VERSION 5.8 ;
BUSBITCHARS "[]" ;
DIVIDERCHAR "/" ;
UNITS
    DATABASE MICRONS 1000 ;
END UNITS

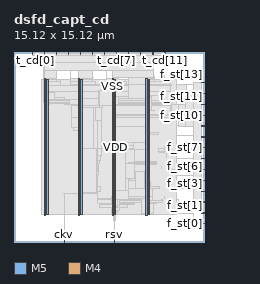
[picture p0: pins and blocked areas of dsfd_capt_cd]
MACRO dsfd_capt_cd
  FOREIGN dsfd_capt_cd 0 0 ;
  CLASS BLOCK ;
  SIZE 15.12 BY 15.12 ;
  PIN ckv
    DIRECTION INPUT ;
    USE SIGNAL ;
    PORT
      LAYER M5 ;
        RECT  3.984 0 4.008 0.192 ;
    END
  END ckv
  PIN f_st[0]
    DIRECTION INPUT ;
    USE SIGNAL ;
    PORT
      LAYER M4 ;
        RECT  14.928 1.44 15.12 1.464 ;
    END
  END f_st[0]
  PIN f_st[10]
    DIRECTION INPUT ;
    USE SIGNAL ;
    PORT
      LAYER M4 ;
        RECT  14.928 10.08 15.12 10.104 ;
    END
  END f_st[10]
  PIN f_st[11]
    DIRECTION INPUT ;
    USE SIGNAL ;
    PORT
      LAYER M4 ;
        RECT  14.928 10.944 15.12 10.968 ;
    END
  END f_st[11]
  PIN f_st[12]
    DIRECTION INPUT ;
    USE SIGNAL ;
    PORT
      LAYER M4 ;
        RECT  14.928 11.808 15.12 11.832 ;
    END
  END f_st[12]
  PIN f_st[13]
    DIRECTION INPUT ;
    USE SIGNAL ;
    PORT
      LAYER M4 ;
        RECT  14.928 12.672 15.12 12.696 ;
    END
  END f_st[13]
  PIN f_st[1]
    DIRECTION INPUT ;
    USE SIGNAL ;
    PORT
      LAYER M4 ;
        RECT  14.928 2.304 15.12 2.328 ;
    END
  END f_st[1]
  PIN f_st[2]
    DIRECTION INPUT ;
    USE SIGNAL ;
    PORT
      LAYER M4 ;
        RECT  14.928 3.168 15.12 3.192 ;
    END
  END f_st[2]
  PIN f_st[3]
    DIRECTION INPUT ;
    USE SIGNAL ;
    PORT
      LAYER M4 ;
        RECT  14.928 4.032 15.12 4.056 ;
    END
  END f_st[3]
  PIN f_st[4]
    DIRECTION INPUT ;
    USE SIGNAL ;
    PORT
      LAYER M4 ;
        RECT  14.928 4.896 15.12 4.92 ;
    END
  END f_st[4]
  PIN f_st[5]
    DIRECTION INPUT ;
    USE SIGNAL ;
    PORT
      LAYER M4 ;
        RECT  14.928 5.76 15.12 5.784 ;
    END
  END f_st[5]
  PIN f_st[6]
    DIRECTION INPUT ;
    USE SIGNAL ;
    PORT
      LAYER M4 ;
        RECT  14.928 6.624 15.12 6.648 ;
    END
  END f_st[6]
  PIN f_st[7]
    DIRECTION INPUT ;
    USE SIGNAL ;
    PORT
      LAYER M4 ;
        RECT  14.928 7.488 15.12 7.512 ;
    END
  END f_st[7]
  PIN f_st[8]
    DIRECTION INPUT ;
    USE SIGNAL ;
    PORT
      LAYER M4 ;
        RECT  14.928 8.352 15.12 8.376 ;
    END
  END f_st[8]
  PIN f_st[9]
    DIRECTION INPUT ;
    USE SIGNAL ;
    PORT
      LAYER M4 ;
        RECT  14.928 9.216 15.12 9.24 ;
    END
  END f_st[9]
  PIN rsv
    DIRECTION INPUT ;
    USE SIGNAL ;
    PORT
      LAYER M5 ;
        RECT  7.968 0 7.992 0.192 ;
    END
  END rsv
  PIN t_cd[0]
    DIRECTION OUTPUT ;
    USE SIGNAL ;
    PORT
      LAYER M5 ;
        RECT  1.44 14.928 1.464 15.12 ;
    END
  END t_cd[0]
  PIN t_cd[10]
    DIRECTION OUTPUT ;
    USE SIGNAL ;
    PORT
      LAYER M5 ;
        RECT  11.04 14.928 11.064 15.12 ;
    END
  END t_cd[10]
  PIN t_cd[11]
    DIRECTION OUTPUT ;
    USE SIGNAL ;
    PORT
      LAYER M5 ;
        RECT  12 14.928 12.024 15.12 ;
    END
  END t_cd[11]
  PIN t_cd[1]
    DIRECTION OUTPUT ;
    USE SIGNAL ;
    PORT
      LAYER M5 ;
        RECT  2.4 14.928 2.424 15.12 ;
    END
  END t_cd[1]
  PIN t_cd[2]
    DIRECTION OUTPUT ;
    USE SIGNAL ;
    PORT
      LAYER M5 ;
        RECT  3.36 14.928 3.384 15.12 ;
    END
  END t_cd[2]
  PIN t_cd[3]
    DIRECTION OUTPUT ;
    USE SIGNAL ;
    PORT
      LAYER M5 ;
        RECT  4.32 14.928 4.344 15.12 ;
    END
  END t_cd[3]
  PIN t_cd[4]
    DIRECTION OUTPUT ;
    USE SIGNAL ;
    PORT
      LAYER M5 ;
        RECT  5.28 14.928 5.304 15.12 ;
    END
  END t_cd[4]
  PIN t_cd[5]
    DIRECTION OUTPUT ;
    USE SIGNAL ;
    PORT
      LAYER M5 ;
        RECT  6.24 14.928 6.264 15.12 ;
    END
  END t_cd[5]
  PIN t_cd[6]
    DIRECTION OUTPUT ;
    USE SIGNAL ;
    PORT
      LAYER M5 ;
        RECT  7.2 14.928 7.224 15.12 ;
    END
  END t_cd[6]
  PIN t_cd[7]
    DIRECTION OUTPUT ;
    USE SIGNAL ;
    PORT
      LAYER M5 ;
        RECT  8.16 14.928 8.184 15.12 ;
    END
  END t_cd[7]
  PIN t_cd[8]
    DIRECTION OUTPUT ;
    USE SIGNAL ;
    PORT
      LAYER M5 ;
        RECT  9.12 14.928 9.144 15.12 ;
    END
  END t_cd[8]
  PIN t_cd[9]
    DIRECTION OUTPUT ;
    USE SIGNAL ;
    PORT
      LAYER M5 ;
        RECT  10.08 14.928 10.104 15.12 ;
    END
  END t_cd[9]
  PIN VDD
    DIRECTION INOUT ;
    USE POWER ;
    PORT
      LAYER M5 ;
        RECT  10.692 2.151 10.812 12.969 ;
        RECT  7.992 2.151 8.112 12.969 ;
        RECT  5.292 2.151 5.412 12.969 ;
        RECT  2.592 2.151 2.712 12.969 ;
    END
  END VDD
  PIN VSS
    DIRECTION INOUT ;
    USE GROUND ;
    PORT
      LAYER M5 ;
        RECT  10.5 2.137 10.62 12.983 ;
        RECT  7.8 2.137 7.92 12.983 ;
        RECT  5.1 2.137 5.22 12.983 ;
        RECT  2.4 2.137 2.52 12.983 ;
    END
  END VSS
  OBS
    LAYER RVTN ;
     RECT  2.16 2.16 12.96 2.295 ;
     RECT  2.16 2.565 12.96 2.835 ;
     RECT  2.16 3.105 12.96 3.375 ;
     RECT  2.16 3.645 12.96 3.915 ;
     RECT  2.16 4.185 12.96 4.455 ;
     RECT  2.16 4.725 12.96 4.995 ;
     RECT  2.16 5.265 12.96 5.535 ;
     RECT  2.16 5.805 12.96 6.075 ;
     RECT  2.16 6.345 12.96 6.615 ;
     RECT  2.16 6.885 12.96 7.155 ;
     RECT  2.16 7.425 12.96 7.695 ;
     RECT  2.16 7.965 12.96 8.235 ;
     RECT  2.16 8.505 12.96 8.775 ;
     RECT  2.16 9.045 12.96 9.315 ;
     RECT  2.16 9.585 12.96 9.855 ;
     RECT  2.16 10.125 12.96 10.395 ;
     RECT  2.16 10.665 12.96 10.935 ;
     RECT  2.16 11.205 12.96 11.475 ;
     RECT  2.16 11.745 12.96 12.015 ;
     RECT  2.16 12.285 12.96 12.555 ;
     RECT  2.16 12.825 12.96 12.96 ;
    LAYER RVTP ;
     RECT  2.16 2.295 12.96 2.565 ;
     RECT  2.16 2.835 12.96 3.105 ;
     RECT  2.16 3.375 12.96 3.645 ;
     RECT  2.16 3.915 12.96 4.185 ;
     RECT  2.16 4.455 12.96 4.725 ;
     RECT  2.16 4.995 12.96 5.265 ;
     RECT  2.16 5.535 12.96 5.805 ;
     RECT  2.16 6.075 12.96 6.345 ;
     RECT  2.16 6.615 12.96 6.885 ;
     RECT  2.16 7.155 12.96 7.425 ;
     RECT  2.16 7.695 12.96 7.965 ;
     RECT  2.16 8.235 12.96 8.505 ;
     RECT  2.16 8.775 12.96 9.045 ;
     RECT  2.16 9.315 12.96 9.585 ;
     RECT  2.16 9.855 12.96 10.125 ;
     RECT  2.16 10.395 12.96 10.665 ;
     RECT  2.16 10.935 12.96 11.205 ;
     RECT  2.16 11.475 12.96 11.745 ;
     RECT  2.16 12.015 12.96 12.285 ;
     RECT  2.16 12.555 12.96 12.825 ;
    LAYER M1 ;
     RECT  2.16 2.151 12.96 12.969 ;
    LAYER M2 ;
     RECT  2.16 2.151 12.96 12.969 ;
     RECT  12.96 3.348 13.127 3.366 ;
     RECT  12.96 9.288 13.127 9.306 ;
     RECT  12.96 11.79 13.703 12.546 ;
     RECT  12.96 2.268 14.279 2.286 ;
     RECT  12.96 4.23 14.279 4.248 ;
     RECT  12.96 5.31 14.279 5.328 ;
     RECT  12.96 6.624 14.279 6.642 ;
     RECT  12.96 7.398 14.279 7.416 ;
     RECT  12.96 8.478 14.279 8.496 ;
     RECT  13.703 12.528 14.279 12.546 ;
    LAYER M3 ;
     RECT  8.028 1.723 8.046 2.143 ;
     RECT  7.815 2.143 8.046 2.191 ;
     RECT  10.515 2.143 10.605 2.191 ;
     RECT  10.515 2.191 10.674 2.227 ;
     RECT  10.188 2.227 11.07 2.285 ;
     RECT  14.256 1.435 14.274 2.291 ;
     RECT  7.74 2.191 8.046 2.371 ;
     RECT  2.415 2.143 2.505 2.413 ;
     RECT  5.115 2.143 5.205 2.413 ;
     RECT  7.74 2.371 8.226 2.533 ;
     RECT  7.74 2.533 8.37 2.767 ;
     RECT  6.84 2.767 9.018 3.001 ;
     RECT  6.84 3.001 9.558 3.029 ;
     RECT  10.332 2.285 11.07 3.037 ;
     RECT  7.38 3.029 9.558 3.065 ;
     RECT  7.56 3.065 9.558 3.101 ;
     RECT  7.74 3.101 9.558 3.109 ;
     RECT  10.332 3.037 11.322 3.109 ;
     RECT  7.74 3.109 11.322 3.181 ;
     RECT  7.74 3.181 11.79 3.335 ;
     RECT  13.104 3.163 13.122 3.371 ;
     RECT  11.772 3.335 11.79 3.407 ;
     RECT  7.74 3.335 11.034 3.605 ;
     RECT  7.815 3.605 8.19 3.641 ;
     RECT  11.952 3.451 11.97 3.641 ;
     RECT  7.815 3.641 8.154 3.749 ;
     RECT  6.624 3.037 6.642 3.835 ;
     RECT  6.336 3.835 6.642 3.875 ;
     RECT  6.552 3.875 6.642 3.965 ;
     RECT  6.624 3.965 6.642 3.991 ;
     RECT  9.108 3.605 11.034 4.261 ;
     RECT  9.108 4.261 11.574 4.289 ;
     RECT  10.404 4.289 11.574 4.379 ;
     RECT  6.624 3.991 6.858 4.415 ;
     RECT  10.404 4.379 10.89 4.793 ;
     RECT  7.815 3.749 8.097 4.891 ;
     RECT  9.108 4.289 9.666 4.891 ;
     RECT  7.815 4.891 9.666 5.027 ;
     RECT  7.815 5.027 8.586 5.213 ;
     RECT  14.256 4.027 14.274 5.333 ;
     RECT  6.624 4.415 6.642 5.341 ;
     RECT  9.612 5.027 9.666 5.611 ;
     RECT  10.404 4.793 10.797 5.611 ;
     RECT  6.588 5.341 6.714 5.639 ;
     RECT  12.564 5.755 12.582 5.801 ;
     RECT  11.736 5.881 11.754 5.999 ;
     RECT  7.815 5.213 8.406 6.151 ;
     RECT  9.612 5.611 10.797 6.151 ;
     RECT  6.624 5.639 6.714 6.241 ;
     RECT  7.815 6.151 8.766 6.241 ;
     RECT  9.612 6.151 11.358 6.241 ;
     RECT  7.815 6.241 11.358 6.269 ;
     RECT  9.144 6.269 11.358 6.341 ;
     RECT  9.612 6.341 11.358 6.413 ;
     RECT  6.624 6.241 6.786 6.511 ;
     RECT  14.256 6.613 14.274 6.653 ;
     RECT  6.624 6.511 6.894 6.853 ;
     RECT  12.132 6.691 12.15 7.079 ;
     RECT  11.592 7.087 11.97 7.231 ;
     RECT  8.856 7.321 8.874 7.387 ;
     RECT  9.612 6.413 10.797 7.387 ;
     RECT  11.52 7.231 11.97 7.421 ;
     RECT  7.815 6.269 8.097 7.435 ;
     RECT  8.856 7.387 10.797 7.435 ;
     RECT  14.256 7.393 14.274 7.517 ;
     RECT  11.952 7.421 11.97 7.619 ;
     RECT  7.815 7.435 10.797 7.655 ;
     RECT  14.256 8.347 14.274 8.501 ;
     RECT  9.072 7.655 10.797 8.581 ;
     RECT  7.815 7.655 8.097 8.671 ;
     RECT  9.072 8.581 11.502 8.735 ;
     RECT  5.115 2.413 5.397 8.851 ;
     RECT  7.815 8.671 8.118 8.851 ;
     RECT  9.072 8.735 10.797 8.851 ;
     RECT  4.752 8.851 5.397 9.085 ;
     RECT  13.104 9.211 13.122 9.311 ;
     RECT  6.624 6.853 7.002 9.661 ;
     RECT  11.7 9.859 11.718 9.895 ;
     RECT  12.492 9.391 12.51 9.895 ;
     RECT  4.572 9.085 5.397 9.931 ;
     RECT  7.815 8.851 10.797 9.931 ;
     RECT  11.7 9.895 12.51 9.931 ;
     RECT  7.815 9.931 12.51 10.075 ;
     RECT  7.815 10.075 12.582 10.121 ;
     RECT  6.48 9.661 7.002 10.741 ;
     RECT  4.572 9.931 5.742 10.831 ;
     RECT  6.48 10.741 7.038 10.831 ;
     RECT  4.572 10.831 7.038 10.843 ;
     RECT  7.815 10.121 12.438 10.843 ;
     RECT  2.415 2.413 2.697 10.939 ;
     RECT  4.572 10.843 12.438 10.939 ;
     RECT  4.392 10.939 12.582 10.975 ;
     RECT  2.415 10.939 2.862 11.011 ;
     RECT  3.996 10.975 12.582 11.011 ;
     RECT  2.415 11.011 12.582 11.101 ;
     RECT  2.34 11.101 12.582 11.237 ;
     RECT  13.68 11.785 13.698 11.837 ;
     RECT  2.34 11.237 12.474 11.975 ;
     RECT  2.376 11.975 12.474 12.451 ;
     RECT  2.376 12.451 12.546 12.479 ;
     RECT  4.464 12.479 12.546 12.551 ;
     RECT  7.38 12.551 12.474 12.557 ;
     RECT  14.256 12.523 14.274 12.701 ;
     RECT  2.376 12.479 3.726 12.749 ;
     RECT  4.464 12.551 6.498 12.749 ;
     RECT  7.38 12.557 8.946 12.749 ;
     RECT  9.684 12.557 12.474 12.749 ;
     RECT  4.464 12.749 6.246 12.785 ;
     RECT  2.376 12.749 2.505 12.901 ;
     RECT  3.384 12.749 3.726 12.929 ;
     RECT  10.188 12.749 11.142 12.929 ;
     RECT  2.34 12.901 2.505 12.977 ;
     RECT  4.464 12.785 5.454 12.977 ;
     RECT  7.38 12.749 8.334 12.977 ;
     RECT  10.515 12.929 11.142 12.977 ;
     RECT  3.384 12.929 3.402 13.085 ;
     RECT  6.228 12.785 6.246 13.085 ;
     RECT  8.316 12.977 8.334 13.133 ;
     RECT  11.124 12.977 11.142 13.133 ;
     RECT  4.464 12.977 4.482 13.661 ;
     RECT  5.436 12.977 5.454 13.661 ;
     RECT  7.38 12.977 7.398 13.661 ;
     RECT  2.34 12.977 2.394 13.901 ;
     RECT  2.376 13.901 2.394 14.285 ;
     RECT  11.988 12.749 12.006 14.909 ;
    LAYER M4 ;
     RECT  1.429 14.256 2.329 14.28 ;
     RECT  2.329 13.872 2.405 14.28 ;
     RECT  2.405 13.872 2.408 13.896 ;
     RECT  2.408 2.148 2.435 13.896 ;
     RECT  2.435 2.148 2.512 13.08 ;
     RECT  2.512 2.418 2.704 13.08 ;
     RECT  2.704 11.376 3.197 11.88 ;
     RECT  2.704 13.056 3.413 13.08 ;
     RECT  3.197 11.376 4.021 11.496 ;
     RECT  4.021 11.28 4.025 11.496 ;
     RECT  4.025 11.28 4.381 11.304 ;
     RECT  3.973 3.84 5.108 3.864 ;
     RECT  4.381 10.944 5.108 11.304 ;
     RECT  4.309 13.632 5.108 13.656 ;
     RECT  5.108 2.148 5.212 13.656 ;
     RECT  5.212 2.418 5.404 13.656 ;
     RECT  5.404 13.056 5.465 13.656 ;
     RECT  5.465 13.056 6.301 13.08 ;
     RECT  5.404 3.84 6.541 3.864 ;
     RECT  6.541 3.84 6.613 3.96 ;
     RECT  6.613 3.408 6.625 3.96 ;
     RECT  5.404 10.848 6.716 11.4 ;
     RECT  6.716 10.752 6.757 11.4 ;
     RECT  6.757 10.752 6.803 12.072 ;
     RECT  7.189 13.632 7.409 13.656 ;
     RECT  6.625 3.408 7.808 3.432 ;
     RECT  6.565 7.44 7.808 7.464 ;
     RECT  6.803 10.848 7.808 12.072 ;
     RECT  7.808 2.148 7.957 13.128 ;
     RECT  7.957 1.728 8.057 13.128 ;
     RECT  8.057 2.418 8.104 13.128 ;
     RECT  8.104 2.832 8.237 5.208 ;
     RECT  8.104 10.944 8.309 11.544 ;
     RECT  8.104 13.104 8.345 13.128 ;
     RECT  8.237 2.928 8.381 5.208 ;
     RECT  8.381 3.408 8.597 5.208 ;
     RECT  8.104 7.344 8.915 7.464 ;
     RECT  8.309 11.424 9.097 11.544 ;
     RECT  9.097 11.424 9.109 11.688 ;
     RECT  8.597 3.408 9.148 5.016 ;
     RECT  9.148 4.992 9.173 5.016 ;
     RECT  8.104 8.688 9.5 9.144 ;
     RECT  8.915 7.392 9.529 7.464 ;
     RECT  9.5 8.688 9.529 9.192 ;
     RECT  10.133 2.256 10.165 2.28 ;
     RECT  9.148 3.408 10.165 3.432 ;
     RECT  10.165 2.256 10.508 3.432 ;
     RECT  9.529 7.392 10.508 9.192 ;
     RECT  9.109 11.424 10.508 12.552 ;
     RECT  10.508 2.148 10.612 12.972 ;
     RECT  10.612 2.418 10.804 12.972 ;
     RECT  10.804 11.52 10.931 11.688 ;
     RECT  11.029 13.104 11.153 13.128 ;
     RECT  10.804 10.464 11.189 10.488 ;
     RECT  10.931 11.664 11.621 11.688 ;
     RECT  11.977 14.88 12.061 14.904 ;
     RECT  12.553 10.08 13.093 10.968 ;
     RECT  13.093 9.216 13.669 10.968 ;
     RECT  13.093 3.168 14.245 3.192 ;
     RECT  12.553 5.76 14.245 5.784 ;
     RECT  13.669 9.216 14.245 11.832 ;
     RECT  14.245 1.44 14.94 1.464 ;
     RECT  14.245 3.168 14.94 12.696 ;
    LAYER M5 ;
     RECT  7.968 0.144 7.992 2.137 ;
     RECT  2.4 2.137 2.52 2.151 ;
     RECT  5.1 2.137 5.22 2.151 ;
     RECT  7.8 2.137 7.992 2.151 ;
     RECT  10.5 2.137 10.62 2.151 ;
     RECT  10.5 2.151 10.812 2.245 ;
     RECT  7.8 2.151 8.112 3.397 ;
     RECT  10.176 2.245 10.812 3.443 ;
     RECT  5.1 2.151 5.412 3.829 ;
     RECT  3.984 0.144 4.008 3.875 ;
     RECT  5.1 3.829 6.36 3.925 ;
     RECT  7.8 3.397 9.096 4.115 ;
     RECT  5.1 3.925 6.6 7.475 ;
     RECT  7.8 4.115 8.904 7.957 ;
     RECT  10.5 3.443 10.812 7.957 ;
     RECT  7.8 7.957 10.812 9.155 ;
     RECT  9.552 9.155 10.812 9.203 ;
     RECT  10.5 9.203 10.812 10.453 ;
     RECT  5.1 7.475 6.36 10.741 ;
     RECT  5.1 10.741 6.792 10.883 ;
     RECT  10.5 10.453 10.92 11.555 ;
     RECT  6.768 10.883 6.792 12.083 ;
     RECT  10.5 11.555 10.812 12.517 ;
     RECT  2.4 2.151 2.712 13.045 ;
     RECT  5.1 10.883 5.412 13.045 ;
     RECT  7.8 9.155 8.112 13.093 ;
     RECT  9.12 12.517 10.812 13.093 ;
     RECT  2.4 13.045 3.384 13.621 ;
     RECT  5.1 13.045 6.264 13.621 ;
     RECT  7.8 13.093 11.064 13.621 ;
     RECT  2.4 13.621 11.064 14.245 ;
     RECT  1.44 14.245 11.064 14.869 ;
     RECT  1.44 14.869 12.024 14.992 ;
  END
END dsfd_capt_cd
END LIBRARY
